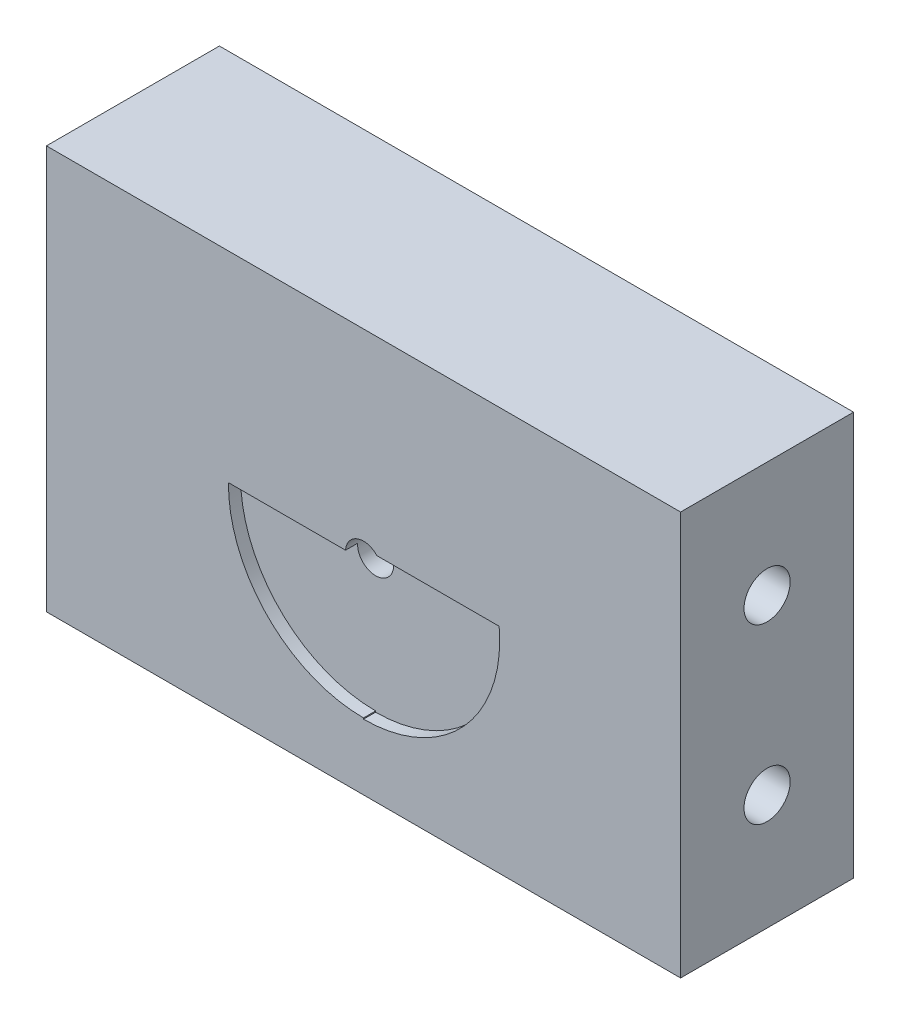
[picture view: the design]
ISO-10303-21;
HEADER;
FILE_DESCRIPTION(('STEP AP214'),'2;1');
FILE_NAME('part.step','',(''),(''),'','','');
FILE_SCHEMA(('AUTOMOTIVE_DESIGN { 1 0 10303 214 1 1 1 1 }'));
ENDSEC;
DATA;
#1=APPLICATION_CONTEXT('core data for automotive mechanical design processes');
#2=APPLICATION_PROTOCOL_DEFINITION('international standard','automotive_design',2000,#1);
#3=PRODUCT_CONTEXT('',#1,'mechanical');
#4=PRODUCT('Part','Part','',(#3));
#5=PRODUCT_RELATED_PRODUCT_CATEGORY('part','',(#4));
#6=PRODUCT_DEFINITION_FORMATION('','',#4);
#7=PRODUCT_DEFINITION_CONTEXT('part definition',#1,'design');
#8=PRODUCT_DEFINITION('design','',#6,#7);
#9=PRODUCT_DEFINITION_SHAPE('','',#8);
#10=(LENGTH_UNIT() NAMED_UNIT(*) SI_UNIT(.MILLI.,.METRE.));
#11=(NAMED_UNIT(*) PLANE_ANGLE_UNIT() SI_UNIT($,.RADIAN.));
#12=(NAMED_UNIT(*) SI_UNIT($,.STERADIAN.) SOLID_ANGLE_UNIT());
#13=UNCERTAINTY_MEASURE_WITH_UNIT(LENGTH_MEASURE(1.E-05),#10,'distance_accuracy_value','');
#14=(GEOMETRIC_REPRESENTATION_CONTEXT(3) GLOBAL_UNCERTAINTY_ASSIGNED_CONTEXT((#13)) GLOBAL_UNIT_ASSIGNED_CONTEXT((#10,
#11,#12)) REPRESENTATION_CONTEXT('',''));
#15=CARTESIAN_POINT('',(0.,0.,0.));
#16=DIRECTION('',(0.,0.,1.));
#17=DIRECTION('',(1.,0.,0.));
#18=AXIS2_PLACEMENT_3D('',#15,#16,#17);
#19=CARTESIAN_POINT('',(0.360795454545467,0.,-6.35));
#20=DIRECTION('',(0.,0.,1.));
#21=DIRECTION('',(1.,0.,0.));
#22=AXIS2_PLACEMENT_3D('',#19,#20,#21);
#23=PLANE('',#22);
#24=CARTESIAN_POINT('',(0.,0.,-6.35000000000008));
#25=DIRECTION('',(0.,0.,-1.));
#26=DIRECTION('',(-1.,0.,0.));
#27=AXIS2_PLACEMENT_3D('',#24,#25,#26);
#28=CIRCLE('',#27,3.96875000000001);
#29=CARTESIAN_POINT('',(-3.96875000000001,0.,-6.35000000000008));
#30=VERTEX_POINT('',#29);
#31=EDGE_CURVE('E154',#30,#30,#28,.F.);
#32=ORIENTED_EDGE('',*,*,#31,.T.);
#33=EDGE_LOOP('',(#32));
#34=FACE_BOUND('',#33,.T.);
#35=ADVANCED_FACE('F33',(#34),#23,.T.);
#36=CARTESIAN_POINT('',(-67.31,0.386772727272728,7.62));
#37=DIRECTION('',(1.,0.,0.));
#38=DIRECTION('',(0.,0.,-1.));
#39=AXIS2_PLACEMENT_3D('',#36,#37,#38);
#40=PLANE('',#39);
#41=CARTESIAN_POINT('',(-67.31,0.,7.62));
#42=DIRECTION('',(1.,0.,0.));
#43=DIRECTION('',(0.,0.,-1.));
#44=AXIS2_PLACEMENT_3D('',#41,#42,#43);
#45=CIRCLE('',#44,4.25450000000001);
#46=CARTESIAN_POINT('',(-67.31,0.,3.36549999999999));
#47=VERTEX_POINT('',#46);
#48=EDGE_CURVE('E292',#47,#47,#45,.F.);
#49=ORIENTED_EDGE('',*,*,#48,.T.);
#50=EDGE_LOOP('',(#49));
#51=FACE_BOUND('',#50,.T.);
#52=ADVANCED_FACE('F321',(#51),#40,.F.);
#53=CARTESIAN_POINT('',(-65.278,-9.80209090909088,0.));
#54=DIRECTION('',(1.,0.,0.));
#55=DIRECTION('',(0.,0.,-1.));
#56=AXIS2_PLACEMENT_3D('',#53,#54,#55);
#57=PLANE('',#56);
#58=CARTESIAN_POINT('',(-65.278,-10.16,0.));
#59=DIRECTION('',(1.,0.,0.));
#60=DIRECTION('',(0.,0.,-1.));
#61=AXIS2_PLACEMENT_3D('',#58,#59,#60);
#62=CIRCLE('',#61,3.93700000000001);
#63=CARTESIAN_POINT('',(-65.278,-10.16,-3.93700000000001));
#64=VERTEX_POINT('',#63);
#65=EDGE_CURVE('E289',#64,#64,#62,.F.);
#66=ORIENTED_EDGE('',*,*,#65,.T.);
#67=EDGE_LOOP('',(#66));
#68=FACE_BOUND('',#67,.T.);
#69=ADVANCED_FACE('F326',(#68),#57,.F.);
#70=CARTESIAN_POINT('',(-65.278,10.5179090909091,0.));
#71=DIRECTION('',(1.,0.,0.));
#72=DIRECTION('',(0.,0.,-1.));
#73=AXIS2_PLACEMENT_3D('',#70,#71,#72);
#74=PLANE('',#73);
#75=CARTESIAN_POINT('',(-65.278,10.16,0.));
#76=DIRECTION('',(1.,0.,0.));
#77=DIRECTION('',(0.,0.,-1.));
#78=AXIS2_PLACEMENT_3D('',#75,#76,#77);
#79=CIRCLE('',#78,3.93700000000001);
#80=CARTESIAN_POINT('',(-65.278,10.16,-3.93700000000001));
#81=VERTEX_POINT('',#80);
#82=EDGE_CURVE('E286',#81,#81,#79,.F.);
#83=ORIENTED_EDGE('',*,*,#82,.T.);
#84=EDGE_LOOP('',(#83));
#85=FACE_BOUND('',#84,.T.);
#86=ADVANCED_FACE('F725',(#85),#74,.F.);
#87=CARTESIAN_POINT('',(-67.31,0.386772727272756,-7.62));
#88=DIRECTION('',(1.,0.,0.));
#89=DIRECTION('',(0.,0.,-1.));
#90=AXIS2_PLACEMENT_3D('',#87,#88,#89);
#91=PLANE('',#90);
#92=CARTESIAN_POINT('',(-67.31,0.,-7.62));
#93=DIRECTION('',(1.,0.,0.));
#94=DIRECTION('',(0.,0.,-1.));
#95=AXIS2_PLACEMENT_3D('',#92,#93,#94);
#96=CIRCLE('',#95,4.25450000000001);
#97=CARTESIAN_POINT('',(-67.31,0.,-11.8745));
#98=VERTEX_POINT('',#97);
#99=EDGE_CURVE('E283',#98,#98,#96,.F.);
#100=ORIENTED_EDGE('',*,*,#99,.T.);
#101=EDGE_LOOP('',(#100));
#102=FACE_BOUND('',#101,.T.);
#103=ADVANCED_FACE('F716',(#102),#91,.F.);
#104=CARTESIAN_POINT('',(-67.31,-39.3007272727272,5.08000000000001));
#105=DIRECTION('',(1.,0.,0.));
#106=DIRECTION('',(0.,0.,-1.));
#107=AXIS2_PLACEMENT_3D('',#104,#105,#106);
#108=PLANE('',#107);
#109=CARTESIAN_POINT('',(-67.31,-39.6875,5.08000000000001));
#110=DIRECTION('',(1.,0.,0.));
#111=DIRECTION('',(0.,0.,-1.));
#112=AXIS2_PLACEMENT_3D('',#109,#110,#111);
#113=CIRCLE('',#112,4.25450000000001);
#114=CARTESIAN_POINT('',(-67.31,-39.6875,0.825500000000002));
#115=VERTEX_POINT('',#114);
#116=EDGE_CURVE('E280',#115,#115,#113,.F.);
#117=ORIENTED_EDGE('',*,*,#116,.T.);
#118=EDGE_LOOP('',(#117));
#119=FACE_BOUND('',#118,.T.);
#120=ADVANCED_FACE('F711',(#119),#108,.F.);
#121=CARTESIAN_POINT('',(-67.31,40.0742727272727,5.08000000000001));
#122=DIRECTION('',(1.,0.,0.));
#123=DIRECTION('',(0.,0.,-1.));
#124=AXIS2_PLACEMENT_3D('',#121,#122,#123);
#125=PLANE('',#124);
#126=CARTESIAN_POINT('',(-67.31,39.6875,5.08000000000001));
#127=DIRECTION('',(1.,0.,0.));
#128=DIRECTION('',(0.,0.,-1.));
#129=AXIS2_PLACEMENT_3D('',#126,#127,#128);
#130=CIRCLE('',#129,4.25450000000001);
#131=CARTESIAN_POINT('',(-67.31,39.6875,0.825500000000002));
#132=VERTEX_POINT('',#131);
#133=EDGE_CURVE('E277',#132,#132,#130,.F.);
#134=ORIENTED_EDGE('',*,*,#133,.T.);
#135=EDGE_LOOP('',(#134));
#136=FACE_BOUND('',#135,.T.);
#137=ADVANCED_FACE('F715',(#136),#125,.F.);
#138=CARTESIAN_POINT('',(-67.31,40.0742727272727,-5.08));
#139=DIRECTION('',(1.,0.,0.));
#140=DIRECTION('',(0.,0.,-1.));
#141=AXIS2_PLACEMENT_3D('',#138,#139,#140);
#142=PLANE('',#141);
#143=CARTESIAN_POINT('',(-67.31,39.6875,-5.08));
#144=DIRECTION('',(1.,0.,0.));
#145=DIRECTION('',(0.,0.,-1.));
#146=AXIS2_PLACEMENT_3D('',#143,#144,#145);
#147=CIRCLE('',#146,4.25450000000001);
#148=CARTESIAN_POINT('',(-67.31,39.6875,-9.33450000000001));
#149=VERTEX_POINT('',#148);
#150=EDGE_CURVE('E274',#149,#149,#147,.F.);
#151=ORIENTED_EDGE('',*,*,#150,.T.);
#152=EDGE_LOOP('',(#151));
#153=FACE_BOUND('',#152,.T.);
#154=ADVANCED_FACE('F770',(#153),#142,.F.);
#155=CARTESIAN_POINT('',(-67.31,-39.3007272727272,-5.08));
#156=DIRECTION('',(1.,0.,0.));
#157=DIRECTION('',(0.,0.,-1.));
#158=AXIS2_PLACEMENT_3D('',#155,#156,#157);
#159=PLANE('',#158);
#160=CARTESIAN_POINT('',(-67.31,-39.6875,-5.08));
#161=DIRECTION('',(1.,0.,0.));
#162=DIRECTION('',(0.,0.,-1.));
#163=AXIS2_PLACEMENT_3D('',#160,#161,#162);
#164=CIRCLE('',#163,4.25450000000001);
#165=CARTESIAN_POINT('',(-67.31,-39.6875,-9.33450000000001));
#166=VERTEX_POINT('',#165);
#167=EDGE_CURVE('E271',#166,#166,#164,.F.);
#168=ORIENTED_EDGE('',*,*,#167,.T.);
#169=EDGE_LOOP('',(#168));
#170=FACE_BOUND('',#169,.T.);
#171=ADVANCED_FACE('F350',(#170),#159,.F.);
#172=CARTESIAN_POINT('',(-66.802,-27.94,5.1816));
#173=DIRECTION('',(1.,0.,0.));
#174=DIRECTION('',(0.,0.,-1.));
#175=AXIS2_PLACEMENT_3D('',#172,#173,#174);
#176=PLANE('',#175);
#177=CARTESIAN_POINT('',(-66.802,-22.86,0.));
#178=DIRECTION('',(1.,0.,0.));
#179=DIRECTION('',(0.,0.,-1.));
#180=AXIS2_PLACEMENT_3D('',#177,#178,#179);
#181=CIRCLE('',#180,5.08);
#182=CARTESIAN_POINT('',(-66.802,-22.86,-5.08));
#183=VERTEX_POINT('',#182);
#184=EDGE_CURVE('E268',#183,#183,#181,.F.);
#185=ORIENTED_EDGE('',*,*,#184,.T.);
#186=EDGE_LOOP('',(#185));
#187=FACE_BOUND('',#186,.T.);
#188=ADVANCED_FACE('F347',(#187),#176,.F.);
#189=CARTESIAN_POINT('',(-66.802,23.3218181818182,0.));
#190=DIRECTION('',(1.,0.,0.));
#191=DIRECTION('',(0.,0.,-1.));
#192=AXIS2_PLACEMENT_3D('',#189,#190,#191);
#193=PLANE('',#192);
#194=CARTESIAN_POINT('',(-66.802,22.86,0.));
#195=DIRECTION('',(1.,0.,0.));
#196=DIRECTION('',(0.,0.,-1.));
#197=AXIS2_PLACEMENT_3D('',#194,#195,#196);
#198=CIRCLE('',#197,5.08);
#199=CARTESIAN_POINT('',(-66.802,22.86,-5.08));
#200=VERTEX_POINT('',#199);
#201=EDGE_CURVE('E265',#200,#200,#198,.F.);
#202=ORIENTED_EDGE('',*,*,#201,.T.);
#203=EDGE_LOOP('',(#202));
#204=FACE_BOUND('',#203,.T.);
#205=ADVANCED_FACE('F316',(#204),#193,.F.);
#206=CARTESIAN_POINT('',(0.,0.,19.05));
#207=DIRECTION('',(0.,0.,-1.));
#208=DIRECTION('',(-1.,0.,0.));
#209=AXIS2_PLACEMENT_3D('',#206,#207,#208);
#210=CYLINDRICAL_SURFACE('',#209,3.96875000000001);
#211=CARTESIAN_POINT('',(0.,0.,19.05));
#212=DIRECTION('',(0.,0.,-1.));
#213=DIRECTION('',(-1.,0.,0.));
#214=AXIS2_PLACEMENT_3D('',#211,#212,#213);
#215=CIRCLE('',#214,3.96875000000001);
#216=CARTESIAN_POINT('',(-3.96061365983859,0.253999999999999,19.05));
#217=VERTEX_POINT('',#216);
#218=CARTESIAN_POINT('',(2.93906236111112,2.667,19.05));
#219=VERTEX_POINT('',#218);
#220=EDGE_CURVE('E263',#217,#219,#215,.T.);
#221=ORIENTED_EDGE('',*,*,#220,.F.);
#222=DIRECTION('',(0.,0.,-1.));
#223=VECTOR('',#222,1.);
#224=CARTESIAN_POINT('',(-3.96061365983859,0.253999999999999,19.05));
#225=LINE('',#224,#223);
#226=CARTESIAN_POINT('',(-3.96061365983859,0.253999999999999,16.383));
#227=VERTEX_POINT('',#226);
#228=EDGE_CURVE('E125',#217,#227,#225,.T.);
#229=ORIENTED_EDGE('',*,*,#228,.T.);
#230=CARTESIAN_POINT('',(0.,0.,16.383));
#231=DIRECTION('',(0.,0.,1.));
#232=DIRECTION('',(1.,0.,0.));
#233=AXIS2_PLACEMENT_3D('',#230,#231,#232);
#234=CIRCLE('',#233,3.96875000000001);
#235=CARTESIAN_POINT('',(2.93906236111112,2.667,16.383));
#236=VERTEX_POINT('',#235);
#237=EDGE_CURVE('E41',#236,#227,#234,.F.);
#238=ORIENTED_EDGE('',*,*,#237,.F.);
#239=DIRECTION('',(0.,0.,-1.));
#240=VECTOR('',#239,1.);
#241=CARTESIAN_POINT('',(2.93906236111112,2.667,19.05));
#242=LINE('',#241,#240);
#243=EDGE_CURVE('E150',#236,#219,#242,.F.);
#244=ORIENTED_EDGE('',*,*,#243,.T.);
#245=EDGE_LOOP('',(#221,#229,#238,#244));
#246=FACE_BOUND('',#245,.T.);
#247=ORIENTED_EDGE('',*,*,#31,.F.);
#248=EDGE_LOOP('',(#247));
#249=FACE_BOUND('',#248,.T.);
#250=ADVANCED_FACE('F312',(#246,#249),#210,.F.);
#251=CARTESIAN_POINT('',(39.116,13.97,5.1816));
#252=DIRECTION('',(1.,0.,0.));
#253=DIRECTION('',(0.,0.,-1.));
#254=AXIS2_PLACEMENT_3D('',#251,#252,#253);
#255=PLANE('',#254);
#256=CARTESIAN_POINT('',(39.116,19.05,0.));
#257=DIRECTION('',(-1.,0.,0.));
#258=DIRECTION('',(0.,0.,1.));
#259=AXIS2_PLACEMENT_3D('',#256,#257,#258);
#260=CIRCLE('',#259,5.08);
#261=CARTESIAN_POINT('',(39.116,19.05,5.08));
#262=VERTEX_POINT('',#261);
#263=EDGE_CURVE('E260',#262,#262,#260,.F.);
#264=ORIENTED_EDGE('',*,*,#263,.T.);
#265=EDGE_LOOP('',(#264));
#266=FACE_BOUND('',#265,.T.);
#267=ADVANCED_FACE('F315',(#266),#255,.T.);
#268=CARTESIAN_POINT('',(39.116,-18.5881818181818,0.));
#269=DIRECTION('',(1.,0.,0.));
#270=DIRECTION('',(0.,0.,-1.));
#271=AXIS2_PLACEMENT_3D('',#268,#269,#270);
#272=PLANE('',#271);
#273=CARTESIAN_POINT('',(39.116,-19.05,0.));
#274=DIRECTION('',(-1.,0.,0.));
#275=DIRECTION('',(0.,0.,1.));
#276=AXIS2_PLACEMENT_3D('',#273,#274,#275);
#277=CIRCLE('',#276,5.08);
#278=CARTESIAN_POINT('',(39.116,-19.05,5.08));
#279=VERTEX_POINT('',#278);
#280=EDGE_CURVE('E158',#279,#279,#277,.F.);
#281=ORIENTED_EDGE('',*,*,#280,.T.);
#282=EDGE_LOOP('',(#281));
#283=FACE_BOUND('',#282,.T.);
#284=ADVANCED_FACE('F353',(#283),#272,.T.);
#285=CARTESIAN_POINT('',(-69.85,0.,7.62));
#286=DIRECTION('',(1.,0.,0.));
#287=DIRECTION('',(0.,0.,-1.));
#288=AXIS2_PLACEMENT_3D('',#285,#286,#287);
#289=CYLINDRICAL_SURFACE('',#288,4.25450000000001);
#290=CARTESIAN_POINT('',(-69.85,0.,7.62));
#291=DIRECTION('',(1.,0.,0.));
#292=DIRECTION('',(0.,0.,-1.));
#293=AXIS2_PLACEMENT_3D('',#290,#291,#292);
#294=CIRCLE('',#293,4.25450000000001);
#295=CARTESIAN_POINT('',(-69.85,0.,3.36549999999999));
#296=VERTEX_POINT('',#295);
#297=EDGE_CURVE('E161',#296,#296,#294,.T.);
#298=ORIENTED_EDGE('',*,*,#297,.F.);
#299=EDGE_LOOP('',(#298));
#300=FACE_BOUND('',#299,.T.);
#301=ORIENTED_EDGE('',*,*,#48,.F.);
#302=EDGE_LOOP('',(#301));
#303=FACE_BOUND('',#302,.T.);
#304=ADVANCED_FACE('F590',(#300,#303),#289,.F.);
#305=CARTESIAN_POINT('',(-69.85,-10.16,0.));
#306=DIRECTION('',(1.,0.,0.));
#307=DIRECTION('',(0.,0.,-1.));
#308=AXIS2_PLACEMENT_3D('',#305,#306,#307);
#309=CYLINDRICAL_SURFACE('',#308,3.93700000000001);
#310=CARTESIAN_POINT('',(-69.85,-10.16,0.));
#311=DIRECTION('',(1.,0.,0.));
#312=DIRECTION('',(0.,0.,-1.));
#313=AXIS2_PLACEMENT_3D('',#310,#311,#312);
#314=CIRCLE('',#313,3.93700000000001);
#315=CARTESIAN_POINT('',(-69.85,-10.16,-3.93700000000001));
#316=VERTEX_POINT('',#315);
#317=EDGE_CURVE('E253',#316,#316,#314,.T.);
#318=ORIENTED_EDGE('',*,*,#317,.F.);
#319=EDGE_LOOP('',(#318));
#320=FACE_BOUND('',#319,.T.);
#321=ORIENTED_EDGE('',*,*,#65,.F.);
#322=EDGE_LOOP('',(#321));
#323=FACE_BOUND('',#322,.T.);
#324=ADVANCED_FACE('F601',(#320,#323),#309,.F.);
#325=CARTESIAN_POINT('',(-69.85,10.16,0.));
#326=DIRECTION('',(1.,0.,0.));
#327=DIRECTION('',(0.,0.,-1.));
#328=AXIS2_PLACEMENT_3D('',#325,#326,#327);
#329=CYLINDRICAL_SURFACE('',#328,3.93700000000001);
#330=CARTESIAN_POINT('',(-69.85,10.16,0.));
#331=DIRECTION('',(1.,0.,0.));
#332=DIRECTION('',(0.,0.,-1.));
#333=AXIS2_PLACEMENT_3D('',#330,#331,#332);
#334=CIRCLE('',#333,3.93700000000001);
#335=CARTESIAN_POINT('',(-69.85,10.16,-3.93700000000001));
#336=VERTEX_POINT('',#335);
#337=EDGE_CURVE('E250',#336,#336,#334,.T.);
#338=ORIENTED_EDGE('',*,*,#337,.F.);
#339=EDGE_LOOP('',(#338));
#340=FACE_BOUND('',#339,.T.);
#341=ORIENTED_EDGE('',*,*,#82,.F.);
#342=EDGE_LOOP('',(#341));
#343=FACE_BOUND('',#342,.T.);
#344=ADVANCED_FACE('F610',(#340,#343),#329,.F.);
#345=CARTESIAN_POINT('',(-69.85,0.,-7.62));
#346=DIRECTION('',(1.,0.,0.));
#347=DIRECTION('',(0.,0.,-1.));
#348=AXIS2_PLACEMENT_3D('',#345,#346,#347);
#349=CYLINDRICAL_SURFACE('',#348,4.25450000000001);
#350=CARTESIAN_POINT('',(-69.85,0.,-7.62));
#351=DIRECTION('',(1.,0.,0.));
#352=DIRECTION('',(0.,0.,-1.));
#353=AXIS2_PLACEMENT_3D('',#350,#351,#352);
#354=CIRCLE('',#353,4.25450000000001);
#355=CARTESIAN_POINT('',(-69.85,0.,-11.8745));
#356=VERTEX_POINT('',#355);
#357=EDGE_CURVE('E247',#356,#356,#354,.T.);
#358=ORIENTED_EDGE('',*,*,#357,.F.);
#359=EDGE_LOOP('',(#358));
#360=FACE_BOUND('',#359,.T.);
#361=ORIENTED_EDGE('',*,*,#99,.F.);
#362=EDGE_LOOP('',(#361));
#363=FACE_BOUND('',#362,.T.);
#364=ADVANCED_FACE('F618',(#360,#363),#349,.F.);
#365=CARTESIAN_POINT('',(-69.85,-39.6875,5.08000000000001));
#366=DIRECTION('',(1.,0.,0.));
#367=DIRECTION('',(0.,0.,-1.));
#368=AXIS2_PLACEMENT_3D('',#365,#366,#367);
#369=CYLINDRICAL_SURFACE('',#368,4.25450000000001);
#370=CARTESIAN_POINT('',(-69.85,-39.6875,5.08000000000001));
#371=DIRECTION('',(1.,0.,0.));
#372=DIRECTION('',(0.,0.,-1.));
#373=AXIS2_PLACEMENT_3D('',#370,#371,#372);
#374=CIRCLE('',#373,4.25450000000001);
#375=CARTESIAN_POINT('',(-69.85,-39.6875,0.825500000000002));
#376=VERTEX_POINT('',#375);
#377=EDGE_CURVE('E244',#376,#376,#374,.T.);
#378=ORIENTED_EDGE('',*,*,#377,.F.);
#379=EDGE_LOOP('',(#378));
#380=FACE_BOUND('',#379,.T.);
#381=ORIENTED_EDGE('',*,*,#116,.F.);
#382=EDGE_LOOP('',(#381));
#383=FACE_BOUND('',#382,.T.);
#384=ADVANCED_FACE('F627',(#380,#383),#369,.F.);
#385=CARTESIAN_POINT('',(-69.85,39.6875,5.08000000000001));
#386=DIRECTION('',(1.,0.,0.));
#387=DIRECTION('',(0.,0.,-1.));
#388=AXIS2_PLACEMENT_3D('',#385,#386,#387);
#389=CYLINDRICAL_SURFACE('',#388,4.25450000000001);
#390=CARTESIAN_POINT('',(-69.85,39.6875,5.08000000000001));
#391=DIRECTION('',(1.,0.,0.));
#392=DIRECTION('',(0.,0.,-1.));
#393=AXIS2_PLACEMENT_3D('',#390,#391,#392);
#394=CIRCLE('',#393,4.25450000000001);
#395=CARTESIAN_POINT('',(-69.85,39.6875,0.825500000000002));
#396=VERTEX_POINT('',#395);
#397=EDGE_CURVE('E241',#396,#396,#394,.T.);
#398=ORIENTED_EDGE('',*,*,#397,.F.);
#399=EDGE_LOOP('',(#398));
#400=FACE_BOUND('',#399,.T.);
#401=ORIENTED_EDGE('',*,*,#133,.F.);
#402=EDGE_LOOP('',(#401));
#403=FACE_BOUND('',#402,.T.);
#404=ADVANCED_FACE('F636',(#400,#403),#389,.F.);
#405=CARTESIAN_POINT('',(-69.85,39.6875,-5.08));
#406=DIRECTION('',(1.,0.,0.));
#407=DIRECTION('',(0.,0.,-1.));
#408=AXIS2_PLACEMENT_3D('',#405,#406,#407);
#409=CYLINDRICAL_SURFACE('',#408,4.25450000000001);
#410=CARTESIAN_POINT('',(-69.85,39.6875,-5.08));
#411=DIRECTION('',(1.,0.,0.));
#412=DIRECTION('',(0.,0.,-1.));
#413=AXIS2_PLACEMENT_3D('',#410,#411,#412);
#414=CIRCLE('',#413,4.25450000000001);
#415=CARTESIAN_POINT('',(-69.85,39.6875,-9.33450000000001));
#416=VERTEX_POINT('',#415);
#417=EDGE_CURVE('E238',#416,#416,#414,.T.);
#418=ORIENTED_EDGE('',*,*,#417,.F.);
#419=EDGE_LOOP('',(#418));
#420=FACE_BOUND('',#419,.T.);
#421=ORIENTED_EDGE('',*,*,#150,.F.);
#422=EDGE_LOOP('',(#421));
#423=FACE_BOUND('',#422,.T.);
#424=ADVANCED_FACE('F366',(#420,#423),#409,.F.);
#425=CARTESIAN_POINT('',(-69.85,-39.6875,-5.08));
#426=DIRECTION('',(1.,0.,0.));
#427=DIRECTION('',(0.,0.,-1.));
#428=AXIS2_PLACEMENT_3D('',#425,#426,#427);
#429=CYLINDRICAL_SURFACE('',#428,4.25450000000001);
#430=CARTESIAN_POINT('',(-69.85,-39.6875,-5.08));
#431=DIRECTION('',(1.,0.,0.));
#432=DIRECTION('',(0.,0.,-1.));
#433=AXIS2_PLACEMENT_3D('',#430,#431,#432);
#434=CIRCLE('',#433,4.25450000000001);
#435=CARTESIAN_POINT('',(-69.85,-39.6875,-9.33450000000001));
#436=VERTEX_POINT('',#435);
#437=EDGE_CURVE('E235',#436,#436,#434,.T.);
#438=ORIENTED_EDGE('',*,*,#437,.F.);
#439=EDGE_LOOP('',(#438));
#440=FACE_BOUND('',#439,.T.);
#441=ORIENTED_EDGE('',*,*,#167,.F.);
#442=EDGE_LOOP('',(#441));
#443=FACE_BOUND('',#442,.T.);
#444=ADVANCED_FACE('F358',(#440,#443),#429,.F.);
#445=CARTESIAN_POINT('',(-69.85,-22.86,0.));
#446=DIRECTION('',(1.,0.,0.));
#447=DIRECTION('',(0.,0.,-1.));
#448=AXIS2_PLACEMENT_3D('',#445,#446,#447);
#449=CYLINDRICAL_SURFACE('',#448,5.08);
#450=ORIENTED_EDGE('',*,*,#184,.F.);
#451=EDGE_LOOP('',(#450));
#452=FACE_BOUND('',#451,.T.);
#453=CARTESIAN_POINT('',(-69.85,-22.86,0.));
#454=DIRECTION('',(1.,0.,0.));
#455=DIRECTION('',(0.,0.,-1.));
#456=AXIS2_PLACEMENT_3D('',#453,#454,#455);
#457=CIRCLE('',#456,5.08);
#458=CARTESIAN_POINT('',(-69.85,-22.86,-5.08));
#459=VERTEX_POINT('',#458);
#460=EDGE_CURVE('E232',#459,#459,#457,.T.);
#461=ORIENTED_EDGE('',*,*,#460,.F.);
#462=EDGE_LOOP('',(#461));
#463=FACE_BOUND('',#462,.T.);
#464=ADVANCED_FACE('F355',(#452,#463),#449,.F.);
#465=CARTESIAN_POINT('',(-69.85,22.86,0.));
#466=DIRECTION('',(1.,0.,0.));
#467=DIRECTION('',(0.,0.,-1.));
#468=AXIS2_PLACEMENT_3D('',#465,#466,#467);
#469=CYLINDRICAL_SURFACE('',#468,5.08);
#470=ORIENTED_EDGE('',*,*,#201,.F.);
#471=EDGE_LOOP('',(#470));
#472=FACE_BOUND('',#471,.T.);
#473=CARTESIAN_POINT('',(-69.85,22.86,0.));
#474=DIRECTION('',(1.,0.,0.));
#475=DIRECTION('',(0.,0.,-1.));
#476=AXIS2_PLACEMENT_3D('',#473,#474,#475);
#477=CIRCLE('',#476,5.08);
#478=CARTESIAN_POINT('',(-69.85,22.86,-5.08));
#479=VERTEX_POINT('',#478);
#480=EDGE_CURVE('E168',#479,#479,#477,.T.);
#481=ORIENTED_EDGE('',*,*,#480,.F.);
#482=EDGE_LOOP('',(#481));
#483=FACE_BOUND('',#482,.T.);
#484=ADVANCED_FACE('F357',(#472,#483),#469,.F.);
#485=CARTESIAN_POINT('',(0.,0.,19.05));
#486=DIRECTION('',(0.,0.,1.));
#487=DIRECTION('',(1.,0.,0.));
#488=AXIS2_PLACEMENT_3D('',#485,#486,#487);
#489=PLANE('',#488);
#490=CARTESIAN_POINT('',(0.,0.,19.05));
#491=DIRECTION('',(0.,0.,1.));
#492=DIRECTION('',(1.,0.,0.));
#493=AXIS2_PLACEMENT_3D('',#490,#491,#492);
#494=CIRCLE('',#493,29.7560228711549);
#495=CARTESIAN_POINT('',(-29.7549387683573,0.253999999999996,19.05));
#496=VERTEX_POINT('',#495);
#497=CARTESIAN_POINT('',(0.,-29.7560228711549,19.05));
#498=VERTEX_POINT('',#497);
#499=EDGE_CURVE('E116',#496,#498,#494,.T.);
#500=ORIENTED_EDGE('',*,*,#499,.F.);
#501=DIRECTION('',(-1.,0.,0.));
#502=VECTOR('',#501,1.);
#503=CARTESIAN_POINT('',(2.93906236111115,0.254,19.05));
#504=LINE('',#503,#502);
#505=EDGE_CURVE('E122',#217,#496,#504,.T.);
#506=ORIENTED_EDGE('',*,*,#505,.F.);
#507=ORIENTED_EDGE('',*,*,#220,.T.);
#508=DIRECTION('',(-1.,0.,0.));
#509=VECTOR('',#508,1.);
#510=CARTESIAN_POINT('',(0.,2.667,19.05));
#511=LINE('',#510,#509);
#512=CARTESIAN_POINT('',(29.8812166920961,2.667,19.05));
#513=VERTEX_POINT('',#512);
#514=EDGE_CURVE('E140',#513,#219,#511,.T.);
#515=ORIENTED_EDGE('',*,*,#514,.F.);
#516=CARTESIAN_POINT('',(0.,0.,19.05));
#517=DIRECTION('',(0.,0.,1.));
#518=DIRECTION('',(1.,0.,0.));
#519=AXIS2_PLACEMENT_3D('',#516,#517,#518);
#520=CIRCLE('',#519,30.);
#521=CARTESIAN_POINT('',(0.,-30.,19.05));
#522=VERTEX_POINT('',#521);
#523=EDGE_CURVE('E56',#522,#513,#520,.T.);
#524=ORIENTED_EDGE('',*,*,#523,.F.);
#525=DIRECTION('',(0.,-1.,0.));
#526=VECTOR('',#525,1.);
#527=CARTESIAN_POINT('',(0.,0.,19.05));
#528=LINE('',#527,#526);
#529=EDGE_CURVE('E193',#498,#522,#528,.T.);
#530=ORIENTED_EDGE('',*,*,#529,.F.);
#531=EDGE_LOOP('',(#500,#506,#507,#515,#524,#530));
#532=FACE_BOUND('',#531,.T.);
#533=DIRECTION('',(0.,1.,0.));
#534=VECTOR('',#533,1.);
#535=CARTESIAN_POINT('',(69.85,44.45,19.05));
#536=LINE('',#535,#534);
#537=CARTESIAN_POINT('',(69.85,44.45,19.05));
#538=VERTEX_POINT('',#537);
#539=CARTESIAN_POINT('',(69.85,-44.45,19.05));
#540=VERTEX_POINT('',#539);
#541=EDGE_CURVE('E165',#538,#540,#536,.F.);
#542=ORIENTED_EDGE('',*,*,#541,.F.);
#543=DIRECTION('',(1.,0.,0.));
#544=VECTOR('',#543,1.);
#545=CARTESIAN_POINT('',(-69.85,44.45,19.05));
#546=LINE('',#545,#544);
#547=CARTESIAN_POINT('',(-69.85,44.45,19.05));
#548=VERTEX_POINT('',#547);
#549=EDGE_CURVE('E155',#548,#538,#546,.T.);
#550=ORIENTED_EDGE('',*,*,#549,.F.);
#551=DIRECTION('',(0.,1.,0.));
#552=VECTOR('',#551,1.);
#553=CARTESIAN_POINT('',(-69.85,-44.45,19.05));
#554=LINE('',#553,#552);
#555=CARTESIAN_POINT('',(-69.85,-44.45,19.05));
#556=VERTEX_POINT('',#555);
#557=EDGE_CURVE('E157',#556,#548,#554,.T.);
#558=ORIENTED_EDGE('',*,*,#557,.F.);
#559=DIRECTION('',(1.,0.,0.));
#560=VECTOR('',#559,1.);
#561=CARTESIAN_POINT('',(69.85,-44.45,19.05));
#562=LINE('',#561,#560);
#563=EDGE_CURVE('E166',#540,#556,#562,.F.);
#564=ORIENTED_EDGE('',*,*,#563,.F.);
#565=EDGE_LOOP('',(#542,#550,#558,#564));
#566=FACE_BOUND('',#565,.T.);
#567=ADVANCED_FACE('F305',(#532,#566),#489,.T.);
#568=CARTESIAN_POINT('',(69.85,19.05,0.));
#569=DIRECTION('',(-1.,0.,0.));
#570=DIRECTION('',(0.,0.,1.));
#571=AXIS2_PLACEMENT_3D('',#568,#569,#570);
#572=CYLINDRICAL_SURFACE('',#571,5.08);
#573=ORIENTED_EDGE('',*,*,#263,.F.);
#574=EDGE_LOOP('',(#573));
#575=FACE_BOUND('',#574,.T.);
#576=CARTESIAN_POINT('',(69.85,19.05,0.));
#577=DIRECTION('',(-1.,0.,0.));
#578=DIRECTION('',(0.,0.,1.));
#579=AXIS2_PLACEMENT_3D('',#576,#577,#578);
#580=CIRCLE('',#579,5.08);
#581=CARTESIAN_POINT('',(69.85,19.05,5.08));
#582=VERTEX_POINT('',#581);
#583=EDGE_CURVE('E172',#582,#582,#580,.T.);
#584=ORIENTED_EDGE('',*,*,#583,.F.);
#585=EDGE_LOOP('',(#584));
#586=FACE_BOUND('',#585,.T.);
#587=ADVANCED_FACE('F35',(#575,#586),#572,.F.);
#588=CARTESIAN_POINT('',(69.85,-19.05,0.));
#589=DIRECTION('',(-1.,0.,0.));
#590=DIRECTION('',(0.,0.,1.));
#591=AXIS2_PLACEMENT_3D('',#588,#589,#590);
#592=CYLINDRICAL_SURFACE('',#591,5.08);
#593=ORIENTED_EDGE('',*,*,#280,.F.);
#594=EDGE_LOOP('',(#593));
#595=FACE_BOUND('',#594,.T.);
#596=CARTESIAN_POINT('',(69.85,-19.05,0.));
#597=DIRECTION('',(-1.,0.,0.));
#598=DIRECTION('',(0.,0.,1.));
#599=AXIS2_PLACEMENT_3D('',#596,#597,#598);
#600=CIRCLE('',#599,5.08);
#601=CARTESIAN_POINT('',(69.85,-19.05,5.08));
#602=VERTEX_POINT('',#601);
#603=EDGE_CURVE('E225',#602,#602,#600,.T.);
#604=ORIENTED_EDGE('',*,*,#603,.F.);
#605=EDGE_LOOP('',(#604));
#606=FACE_BOUND('',#605,.T.);
#607=ADVANCED_FACE('F417',(#595,#606),#592,.F.);
#608=CARTESIAN_POINT('',(-37.7392045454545,38.1,-0.1524));
#609=DIRECTION('',(0.,0.,1.));
#610=DIRECTION('',(1.,0.,0.));
#611=AXIS2_PLACEMENT_3D('',#608,#609,#610);
#612=PLANE('',#611);
#613=CARTESIAN_POINT('',(-38.1,38.1,-0.1524));
#614=DIRECTION('',(0.,0.,-1.));
#615=DIRECTION('',(-1.,0.,0.));
#616=AXIS2_PLACEMENT_3D('',#613,#614,#615);
#617=CIRCLE('',#616,3.96875);
#618=CARTESIAN_POINT('',(-42.06875,38.1,-0.1524));
#619=VERTEX_POINT('',#618);
#620=EDGE_CURVE('E222',#619,#619,#617,.T.);
#621=ORIENTED_EDGE('',*,*,#620,.T.);
#622=EDGE_LOOP('',(#621));
#623=FACE_BOUND('',#622,.T.);
#624=ADVANCED_FACE('F422',(#623),#612,.F.);
#625=CARTESIAN_POINT('',(38.4607954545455,38.1,-0.1524));
#626=DIRECTION('',(0.,0.,1.));
#627=DIRECTION('',(1.,0.,0.));
#628=AXIS2_PLACEMENT_3D('',#625,#626,#627);
#629=PLANE('',#628);
#630=CARTESIAN_POINT('',(38.1,38.1,-0.1524));
#631=DIRECTION('',(0.,0.,-1.));
#632=DIRECTION('',(-1.,0.,0.));
#633=AXIS2_PLACEMENT_3D('',#630,#631,#632);
#634=CIRCLE('',#633,3.96875);
#635=CARTESIAN_POINT('',(34.13125,38.1,-0.1524));
#636=VERTEX_POINT('',#635);
#637=EDGE_CURVE('E219',#636,#636,#634,.T.);
#638=ORIENTED_EDGE('',*,*,#637,.T.);
#639=EDGE_LOOP('',(#638));
#640=FACE_BOUND('',#639,.T.);
#641=ADVANCED_FACE('F426',(#640),#629,.F.);
#642=CARTESIAN_POINT('',(-37.7392045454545,-38.1,-0.1524));
#643=DIRECTION('',(0.,0.,1.));
#644=DIRECTION('',(1.,0.,0.));
#645=AXIS2_PLACEMENT_3D('',#642,#643,#644);
#646=PLANE('',#645);
#647=CARTESIAN_POINT('',(-38.1,-38.1,-0.1524));
#648=DIRECTION('',(0.,0.,-1.));
#649=DIRECTION('',(-1.,0.,0.));
#650=AXIS2_PLACEMENT_3D('',#647,#648,#649);
#651=CIRCLE('',#650,3.96875);
#652=CARTESIAN_POINT('',(-42.06875,-38.1,-0.1524));
#653=VERTEX_POINT('',#652);
#654=EDGE_CURVE('E216',#653,#653,#651,.T.);
#655=ORIENTED_EDGE('',*,*,#654,.T.);
#656=EDGE_LOOP('',(#655));
#657=FACE_BOUND('',#656,.T.);
#658=ADVANCED_FACE('F430',(#657),#646,.F.);
#659=CARTESIAN_POINT('',(0.,0.,-3.5814));
#660=DIRECTION('',(0.,0.,1.));
#661=DIRECTION('',(1.,0.,0.));
#662=AXIS2_PLACEMENT_3D('',#659,#660,#661);
#663=PLANE('',#662);
#664=CARTESIAN_POINT('',(-38.1,0.,-3.5814));
#665=DIRECTION('',(0.,0.,-1.));
#666=DIRECTION('',(-1.,0.,0.));
#667=AXIS2_PLACEMENT_3D('',#664,#665,#666);
#668=CIRCLE('',#667,3.98145);
#669=CARTESIAN_POINT('',(-42.08145,0.,-3.5814));
#670=VERTEX_POINT('',#669);
#671=EDGE_CURVE('E213',#670,#670,#668,.T.);
#672=ORIENTED_EDGE('',*,*,#671,.T.);
#673=EDGE_LOOP('',(#672));
#674=FACE_BOUND('',#673,.T.);
#675=ADVANCED_FACE('F434',(#674),#663,.F.);
#676=CARTESIAN_POINT('',(38.4607954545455,-38.1,-0.1524));
#677=DIRECTION('',(0.,0.,1.));
#678=DIRECTION('',(1.,0.,0.));
#679=AXIS2_PLACEMENT_3D('',#676,#677,#678);
#680=PLANE('',#679);
#681=CARTESIAN_POINT('',(38.1,-38.1,-0.1524));
#682=DIRECTION('',(0.,0.,-1.));
#683=DIRECTION('',(-1.,0.,0.));
#684=AXIS2_PLACEMENT_3D('',#681,#682,#683);
#685=CIRCLE('',#684,3.96875);
#686=CARTESIAN_POINT('',(34.13125,-38.1,-0.1524));
#687=VERTEX_POINT('',#686);
#688=EDGE_CURVE('E189',#687,#687,#685,.T.);
#689=ORIENTED_EDGE('',*,*,#688,.T.);
#690=EDGE_LOOP('',(#689));
#691=FACE_BOUND('',#690,.T.);
#692=ADVANCED_FACE('F438',(#691),#680,.F.);
#693=CARTESIAN_POINT('',(-69.85,44.45,-3.5814));
#694=DIRECTION('',(0.,1.,0.));
#695=DIRECTION('',(0.,0.,1.));
#696=AXIS2_PLACEMENT_3D('',#693,#694,#695);
#697=PLANE('',#696);
#698=DIRECTION('',(1.,0.,0.));
#699=VECTOR('',#698,1.);
#700=CARTESIAN_POINT('',(0.,44.45,-19.05));
#701=LINE('',#700,#699);
#702=CARTESIAN_POINT('',(69.85,44.45,-19.05));
#703=VERTEX_POINT('',#702);
#704=CARTESIAN_POINT('',(-69.85,44.45,-19.05));
#705=VERTEX_POINT('',#704);
#706=EDGE_CURVE('E186',#703,#705,#701,.F.);
#707=ORIENTED_EDGE('',*,*,#706,.T.);
#708=DIRECTION('',(0.,0.,1.));
#709=VECTOR('',#708,1.);
#710=CARTESIAN_POINT('',(-69.85,44.45,-3.5814));
#711=LINE('',#710,#709);
#712=EDGE_CURVE('E159',#548,#705,#711,.F.);
#713=ORIENTED_EDGE('',*,*,#712,.F.);
#714=ORIENTED_EDGE('',*,*,#549,.T.);
#715=DIRECTION('',(0.,0.,-1.));
#716=VECTOR('',#715,1.);
#717=CARTESIAN_POINT('',(69.85,44.45,-3.5814));
#718=LINE('',#717,#716);
#719=EDGE_CURVE('E169',#703,#538,#718,.F.);
#720=ORIENTED_EDGE('',*,*,#719,.F.);
#721=EDGE_LOOP('',(#707,#713,#714,#720));
#722=FACE_BOUND('',#721,.T.);
#723=ADVANCED_FACE('F377',(#722),#697,.T.);
#724=CARTESIAN_POINT('',(-69.85,-44.45,-3.5814));
#725=DIRECTION('',(-1.,0.,0.));
#726=DIRECTION('',(0.,0.,1.));
#727=AXIS2_PLACEMENT_3D('',#724,#725,#726);
#728=PLANE('',#727);
#729=ORIENTED_EDGE('',*,*,#480,.T.);
#730=EDGE_LOOP('',(#729));
#731=FACE_BOUND('',#730,.T.);
#732=ORIENTED_EDGE('',*,*,#460,.T.);
#733=EDGE_LOOP('',(#732));
#734=FACE_BOUND('',#733,.T.);
#735=ORIENTED_EDGE('',*,*,#437,.T.);
#736=EDGE_LOOP('',(#735));
#737=FACE_BOUND('',#736,.T.);
#738=ORIENTED_EDGE('',*,*,#417,.T.);
#739=EDGE_LOOP('',(#738));
#740=FACE_BOUND('',#739,.T.);
#741=ORIENTED_EDGE('',*,*,#397,.T.);
#742=EDGE_LOOP('',(#741));
#743=FACE_BOUND('',#742,.T.);
#744=ORIENTED_EDGE('',*,*,#377,.T.);
#745=EDGE_LOOP('',(#744));
#746=FACE_BOUND('',#745,.T.);
#747=ORIENTED_EDGE('',*,*,#357,.T.);
#748=EDGE_LOOP('',(#747));
#749=FACE_BOUND('',#748,.T.);
#750=ORIENTED_EDGE('',*,*,#337,.T.);
#751=EDGE_LOOP('',(#750));
#752=FACE_BOUND('',#751,.T.);
#753=ORIENTED_EDGE('',*,*,#317,.T.);
#754=EDGE_LOOP('',(#753));
#755=FACE_BOUND('',#754,.T.);
#756=ORIENTED_EDGE('',*,*,#297,.T.);
#757=EDGE_LOOP('',(#756));
#758=FACE_BOUND('',#757,.T.);
#759=DIRECTION('',(0.,1.,0.));
#760=VECTOR('',#759,1.);
#761=CARTESIAN_POINT('',(-69.85,0.,-19.05));
#762=LINE('',#761,#760);
#763=CARTESIAN_POINT('',(-69.85,-44.45,-19.05));
#764=VERTEX_POINT('',#763);
#765=EDGE_CURVE('E183',#705,#764,#762,.F.);
#766=ORIENTED_EDGE('',*,*,#765,.T.);
#767=DIRECTION('',(0.,0.,-1.));
#768=VECTOR('',#767,1.);
#769=CARTESIAN_POINT('',(-69.85,-44.45,-3.5814));
#770=LINE('',#769,#768);
#771=EDGE_CURVE('E163',#556,#764,#770,.T.);
#772=ORIENTED_EDGE('',*,*,#771,.F.);
#773=ORIENTED_EDGE('',*,*,#557,.T.);
#774=ORIENTED_EDGE('',*,*,#712,.T.);
#775=EDGE_LOOP('',(#766,#772,#773,#774));
#776=FACE_BOUND('',#775,.T.);
#777=ADVANCED_FACE('F373',(#731,#734,#737,#740,#743,#746,#749,#752,#755,#758,#776),#728,.T.);
#778=CARTESIAN_POINT('',(69.85,-44.45,-3.5814));
#779=DIRECTION('',(0.,-1.,0.));
#780=DIRECTION('',(0.,0.,-1.));
#781=AXIS2_PLACEMENT_3D('',#778,#779,#780);
#782=PLANE('',#781);
#783=DIRECTION('',(1.,0.,0.));
#784=VECTOR('',#783,1.);
#785=CARTESIAN_POINT('',(0.,-44.45,-19.05));
#786=LINE('',#785,#784);
#787=CARTESIAN_POINT('',(69.85,-44.45,-19.05));
#788=VERTEX_POINT('',#787);
#789=EDGE_CURVE('E180',#764,#788,#786,.T.);
#790=ORIENTED_EDGE('',*,*,#789,.T.);
#791=DIRECTION('',(0.,0.,-1.));
#792=VECTOR('',#791,1.);
#793=CARTESIAN_POINT('',(69.85,-44.45,-3.5814));
#794=LINE('',#793,#792);
#795=EDGE_CURVE('E173',#540,#788,#794,.T.);
#796=ORIENTED_EDGE('',*,*,#795,.F.);
#797=ORIENTED_EDGE('',*,*,#563,.T.);
#798=ORIENTED_EDGE('',*,*,#771,.T.);
#799=EDGE_LOOP('',(#790,#796,#797,#798));
#800=FACE_BOUND('',#799,.T.);
#801=ADVANCED_FACE('F376',(#800),#782,.T.);
#802=CARTESIAN_POINT('',(69.85,44.45,-3.5814));
#803=DIRECTION('',(1.,0.,0.));
#804=DIRECTION('',(0.,0.,-1.));
#805=AXIS2_PLACEMENT_3D('',#802,#803,#804);
#806=PLANE('',#805);
#807=ORIENTED_EDGE('',*,*,#603,.T.);
#808=EDGE_LOOP('',(#807));
#809=FACE_BOUND('',#808,.T.);
#810=ORIENTED_EDGE('',*,*,#583,.T.);
#811=EDGE_LOOP('',(#810));
#812=FACE_BOUND('',#811,.T.);
#813=DIRECTION('',(0.,1.,0.));
#814=VECTOR('',#813,1.);
#815=CARTESIAN_POINT('',(69.85,0.,-19.05));
#816=LINE('',#815,#814);
#817=EDGE_CURVE('E176',#788,#703,#816,.T.);
#818=ORIENTED_EDGE('',*,*,#817,.T.);
#819=ORIENTED_EDGE('',*,*,#719,.T.);
#820=ORIENTED_EDGE('',*,*,#541,.T.);
#821=ORIENTED_EDGE('',*,*,#795,.T.);
#822=EDGE_LOOP('',(#818,#819,#820,#821));
#823=FACE_BOUND('',#822,.T.);
#824=ADVANCED_FACE('F407',(#809,#812,#823),#806,.T.);
#825=CARTESIAN_POINT('',(-38.1,38.1,-0.1524));
#826=DIRECTION('',(0.,0.,-1.));
#827=DIRECTION('',(-1.,0.,0.));
#828=AXIS2_PLACEMENT_3D('',#825,#826,#827);
#829=CYLINDRICAL_SURFACE('',#828,3.96875);
#830=CARTESIAN_POINT('',(-38.1,38.1,-19.05));
#831=DIRECTION('',(0.,0.,-1.));
#832=DIRECTION('',(-1.,0.,0.));
#833=AXIS2_PLACEMENT_3D('',#830,#831,#832);
#834=CIRCLE('',#833,3.96875);
#835=CARTESIAN_POINT('',(-42.06875,38.1,-19.05));
#836=VERTEX_POINT('',#835);
#837=EDGE_CURVE('E179',#836,#836,#834,.T.);
#838=ORIENTED_EDGE('',*,*,#837,.T.);
#839=EDGE_LOOP('',(#838));
#840=FACE_BOUND('',#839,.T.);
#841=ORIENTED_EDGE('',*,*,#620,.F.);
#842=EDGE_LOOP('',(#841));
#843=FACE_BOUND('',#842,.T.);
#844=ADVANCED_FACE('F449',(#840,#843),#829,.F.);
#845=CARTESIAN_POINT('',(38.1,38.1,-0.1524));
#846=DIRECTION('',(0.,0.,-1.));
#847=DIRECTION('',(-1.,0.,0.));
#848=AXIS2_PLACEMENT_3D('',#845,#846,#847);
#849=CYLINDRICAL_SURFACE('',#848,3.96875);
#850=CARTESIAN_POINT('',(38.1,38.1,-19.05));
#851=DIRECTION('',(0.,0.,-1.));
#852=DIRECTION('',(-1.,0.,0.));
#853=AXIS2_PLACEMENT_3D('',#850,#851,#852);
#854=CIRCLE('',#853,3.96875);
#855=CARTESIAN_POINT('',(34.13125,38.1,-19.05));
#856=VERTEX_POINT('',#855);
#857=EDGE_CURVE('E206',#856,#856,#854,.T.);
#858=ORIENTED_EDGE('',*,*,#857,.T.);
#859=EDGE_LOOP('',(#858));
#860=FACE_BOUND('',#859,.T.);
#861=ORIENTED_EDGE('',*,*,#637,.F.);
#862=EDGE_LOOP('',(#861));
#863=FACE_BOUND('',#862,.T.);
#864=ADVANCED_FACE('F453',(#860,#863),#849,.F.);
#865=CARTESIAN_POINT('',(-38.1,-38.1,-0.1524));
#866=DIRECTION('',(0.,0.,-1.));
#867=DIRECTION('',(-1.,0.,0.));
#868=AXIS2_PLACEMENT_3D('',#865,#866,#867);
#869=CYLINDRICAL_SURFACE('',#868,3.96875);
#870=CARTESIAN_POINT('',(-38.1,-38.1,-19.05));
#871=DIRECTION('',(0.,0.,-1.));
#872=DIRECTION('',(-1.,0.,0.));
#873=AXIS2_PLACEMENT_3D('',#870,#871,#872);
#874=CIRCLE('',#873,3.96875);
#875=CARTESIAN_POINT('',(-42.06875,-38.1,-19.05));
#876=VERTEX_POINT('',#875);
#877=EDGE_CURVE('E203',#876,#876,#874,.T.);
#878=ORIENTED_EDGE('',*,*,#877,.T.);
#879=EDGE_LOOP('',(#878));
#880=FACE_BOUND('',#879,.T.);
#881=ORIENTED_EDGE('',*,*,#654,.F.);
#882=EDGE_LOOP('',(#881));
#883=FACE_BOUND('',#882,.T.);
#884=ADVANCED_FACE('F457',(#880,#883),#869,.F.);
#885=CARTESIAN_POINT('',(-38.1,0.,-3.5814));
#886=DIRECTION('',(0.,0.,-1.));
#887=DIRECTION('',(-1.,0.,0.));
#888=AXIS2_PLACEMENT_3D('',#885,#886,#887);
#889=CYLINDRICAL_SURFACE('',#888,3.98145);
#890=CARTESIAN_POINT('',(-38.1,0.,-19.05));
#891=DIRECTION('',(0.,0.,-1.));
#892=DIRECTION('',(-1.,0.,0.));
#893=AXIS2_PLACEMENT_3D('',#890,#891,#892);
#894=CIRCLE('',#893,3.98145);
#895=CARTESIAN_POINT('',(-42.08145,0.,-19.05));
#896=VERTEX_POINT('',#895);
#897=EDGE_CURVE('E200',#896,#896,#894,.T.);
#898=ORIENTED_EDGE('',*,*,#897,.T.);
#899=EDGE_LOOP('',(#898));
#900=FACE_BOUND('',#899,.T.);
#901=ORIENTED_EDGE('',*,*,#671,.F.);
#902=EDGE_LOOP('',(#901));
#903=FACE_BOUND('',#902,.T.);
#904=ADVANCED_FACE('F461',(#900,#903),#889,.F.);
#905=CARTESIAN_POINT('',(38.1,-38.1,-0.1524));
#906=DIRECTION('',(0.,0.,-1.));
#907=DIRECTION('',(-1.,0.,0.));
#908=AXIS2_PLACEMENT_3D('',#905,#906,#907);
#909=CYLINDRICAL_SURFACE('',#908,3.96875);
#910=CARTESIAN_POINT('',(38.1,-38.1,-19.05));
#911=DIRECTION('',(0.,0.,-1.));
#912=DIRECTION('',(-1.,0.,0.));
#913=AXIS2_PLACEMENT_3D('',#910,#911,#912);
#914=CIRCLE('',#913,3.96875);
#915=CARTESIAN_POINT('',(34.13125,-38.1,-19.05));
#916=VERTEX_POINT('',#915);
#917=EDGE_CURVE('E197',#916,#916,#914,.T.);
#918=ORIENTED_EDGE('',*,*,#917,.T.);
#919=EDGE_LOOP('',(#918));
#920=FACE_BOUND('',#919,.T.);
#921=ORIENTED_EDGE('',*,*,#688,.F.);
#922=EDGE_LOOP('',(#921));
#923=FACE_BOUND('',#922,.T.);
#924=ADVANCED_FACE('F465',(#920,#923),#909,.F.);
#925=CARTESIAN_POINT('',(0.,0.,-3.5814));
#926=DIRECTION('',(0.,0.,1.));
#927=DIRECTION('',(1.,0.,0.));
#928=AXIS2_PLACEMENT_3D('',#925,#926,#927);
#929=PLANE('',#928);
#930=CARTESIAN_POINT('',(38.1,0.,-3.5814));
#931=DIRECTION('',(0.,0.,-1.));
#932=DIRECTION('',(-1.,0.,0.));
#933=AXIS2_PLACEMENT_3D('',#930,#931,#932);
#934=CIRCLE('',#933,3.98145);
#935=CARTESIAN_POINT('',(34.11855,0.,-3.5814));
#936=VERTEX_POINT('',#935);
#937=EDGE_CURVE('E194',#936,#936,#934,.T.);
#938=ORIENTED_EDGE('',*,*,#937,.T.);
#939=EDGE_LOOP('',(#938));
#940=FACE_BOUND('',#939,.T.);
#941=ADVANCED_FACE('F340',(#940),#929,.F.);
#942=CARTESIAN_POINT('',(0.,0.,-19.05));
#943=DIRECTION('',(0.,0.,1.));
#944=DIRECTION('',(1.,0.,0.));
#945=AXIS2_PLACEMENT_3D('',#942,#943,#944);
#946=PLANE('',#945);
#947=CARTESIAN_POINT('',(-19.05,0.,-19.05));
#948=DIRECTION('',(0.,0.,-1.));
#949=DIRECTION('',(1.,0.,0.));
#950=AXIS2_PLACEMENT_3D('',#947,#948,#949);
#951=CIRCLE('',#950,3.175);
#952=CARTESIAN_POINT('',(-15.875,0.,-19.05));
#953=VERTEX_POINT('',#952);
#954=EDGE_CURVE('E904',#953,#953,#951,.T.);
#955=ORIENTED_EDGE('',*,*,#954,.F.);
#956=EDGE_LOOP('',(#955));
#957=FACE_BOUND('',#956,.T.);
#958=CARTESIAN_POINT('',(19.05,0.,-19.05));
#959=DIRECTION('',(0.,0.,-1.));
#960=DIRECTION('',(-1.,0.,0.));
#961=AXIS2_PLACEMENT_3D('',#958,#959,#960);
#962=CIRCLE('',#961,3.175);
#963=CARTESIAN_POINT('',(15.875,0.,-19.05));
#964=VERTEX_POINT('',#963);
#965=EDGE_CURVE('E903',#964,#964,#962,.T.);
#966=ORIENTED_EDGE('',*,*,#965,.F.);
#967=EDGE_LOOP('',(#966));
#968=FACE_BOUND('',#967,.T.);
#969=ORIENTED_EDGE('',*,*,#917,.F.);
#970=EDGE_LOOP('',(#969));
#971=FACE_BOUND('',#970,.T.);
#972=ORIENTED_EDGE('',*,*,#897,.F.);
#973=EDGE_LOOP('',(#972));
#974=FACE_BOUND('',#973,.T.);
#975=ORIENTED_EDGE('',*,*,#877,.F.);
#976=EDGE_LOOP('',(#975));
#977=FACE_BOUND('',#976,.T.);
#978=ORIENTED_EDGE('',*,*,#857,.F.);
#979=EDGE_LOOP('',(#978));
#980=FACE_BOUND('',#979,.T.);
#981=ORIENTED_EDGE('',*,*,#837,.F.);
#982=EDGE_LOOP('',(#981));
#983=FACE_BOUND('',#982,.T.);
#984=CARTESIAN_POINT('',(38.1,0.,-19.05));
#985=DIRECTION('',(0.,0.,-1.));
#986=DIRECTION('',(-1.,0.,0.));
#987=AXIS2_PLACEMENT_3D('',#984,#985,#986);
#988=CIRCLE('',#987,3.98145);
#989=CARTESIAN_POINT('',(34.11855,0.,-19.05));
#990=VERTEX_POINT('',#989);
#991=EDGE_CURVE('E190',#990,#990,#988,.F.);
#992=ORIENTED_EDGE('',*,*,#991,.T.);
#993=EDGE_LOOP('',(#992));
#994=FACE_BOUND('',#993,.T.);
#995=ORIENTED_EDGE('',*,*,#789,.F.);
#996=ORIENTED_EDGE('',*,*,#765,.F.);
#997=ORIENTED_EDGE('',*,*,#706,.F.);
#998=ORIENTED_EDGE('',*,*,#817,.F.);
#999=EDGE_LOOP('',(#995,#996,#997,#998));
#1000=FACE_BOUND('',#999,.T.);
#1001=ADVANCED_FACE('F334',(#957,#968,#971,#974,#977,#980,#983,#994,#1000),#946,.F.);
#1002=CARTESIAN_POINT('',(38.1,0.,-3.5814));
#1003=DIRECTION('',(0.,0.,-1.));
#1004=DIRECTION('',(-1.,0.,0.));
#1005=AXIS2_PLACEMENT_3D('',#1002,#1003,#1004);
#1006=CYLINDRICAL_SURFACE('',#1005,3.98145);
#1007=ORIENTED_EDGE('',*,*,#991,.F.);
#1008=EDGE_LOOP('',(#1007));
#1009=FACE_BOUND('',#1008,.T.);
#1010=ORIENTED_EDGE('',*,*,#937,.F.);
#1011=EDGE_LOOP('',(#1010));
#1012=FACE_BOUND('',#1011,.T.);
#1013=ADVANCED_FACE('F331',(#1009,#1012),#1006,.F.);
#1014=CARTESIAN_POINT('',(0.,0.,16.383));
#1015=DIRECTION('',(0.,0.,1.));
#1016=DIRECTION('',(1.,0.,0.));
#1017=AXIS2_PLACEMENT_3D('',#1014,#1015,#1016);
#1018=PLANE('',#1017);
#1019=ORIENTED_EDGE('',*,*,#237,.T.);
#1020=DIRECTION('',(-1.,0.,0.));
#1021=VECTOR('',#1020,1.);
#1022=CARTESIAN_POINT('',(2.93906236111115,0.254,16.383));
#1023=LINE('',#1022,#1021);
#1024=CARTESIAN_POINT('',(-29.7549387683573,0.253999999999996,16.383));
#1025=VERTEX_POINT('',#1024);
#1026=EDGE_CURVE('E109',#227,#1025,#1023,.T.);
#1027=ORIENTED_EDGE('',*,*,#1026,.T.);
#1028=CARTESIAN_POINT('',(0.,0.,16.383));
#1029=DIRECTION('',(0.,0.,1.));
#1030=DIRECTION('',(1.,0.,0.));
#1031=AXIS2_PLACEMENT_3D('',#1028,#1029,#1030);
#1032=CIRCLE('',#1031,29.7560228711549);
#1033=CARTESIAN_POINT('',(0.,-29.7560228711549,16.383));
#1034=VERTEX_POINT('',#1033);
#1035=EDGE_CURVE('E48',#1025,#1034,#1032,.T.);
#1036=ORIENTED_EDGE('',*,*,#1035,.T.);
#1037=DIRECTION('',(0.,-1.,0.));
#1038=VECTOR('',#1037,1.);
#1039=CARTESIAN_POINT('',(0.,2.667,16.383));
#1040=LINE('',#1039,#1038);
#1041=CARTESIAN_POINT('',(0.,-30.,16.383));
#1042=VERTEX_POINT('',#1041);
#1043=EDGE_CURVE('E142',#1034,#1042,#1040,.T.);
#1044=ORIENTED_EDGE('',*,*,#1043,.T.);
#1045=CARTESIAN_POINT('',(0.,0.,16.383));
#1046=DIRECTION('',(0.,0.,1.));
#1047=DIRECTION('',(1.,0.,0.));
#1048=AXIS2_PLACEMENT_3D('',#1045,#1046,#1047);
#1049=CIRCLE('',#1048,30.);
#1050=CARTESIAN_POINT('',(29.8812166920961,2.667,16.383));
#1051=VERTEX_POINT('',#1050);
#1052=EDGE_CURVE('E136',#1042,#1051,#1049,.T.);
#1053=ORIENTED_EDGE('',*,*,#1052,.T.);
#1054=DIRECTION('',(-1.,0.,0.));
#1055=VECTOR('',#1054,1.);
#1056=CARTESIAN_POINT('',(0.,2.667,16.383));
#1057=LINE('',#1056,#1055);
#1058=EDGE_CURVE('E139',#1051,#236,#1057,.T.);
#1059=ORIENTED_EDGE('',*,*,#1058,.T.);
#1060=EDGE_LOOP('',(#1019,#1027,#1036,#1044,#1053,#1059));
#1061=FACE_BOUND('',#1060,.T.);
#1062=ADVANCED_FACE('F111',(#1061),#1018,.T.);
#1063=CARTESIAN_POINT('',(0.,2.667,16.383));
#1064=DIRECTION('',(-1.,0.,0.));
#1065=DIRECTION('',(0.,0.,1.));
#1066=AXIS2_PLACEMENT_3D('',#1063,#1064,#1065);
#1067=PLANE('',#1066);
#1068=ORIENTED_EDGE('',*,*,#1043,.F.);
#1069=DIRECTION('',(0.,0.,1.));
#1070=VECTOR('',#1069,1.);
#1071=CARTESIAN_POINT('',(0.,-29.7560228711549,16.383));
#1072=LINE('',#1071,#1070);
#1073=EDGE_CURVE('E11',#1034,#498,#1072,.T.);
#1074=ORIENTED_EDGE('',*,*,#1073,.T.);
#1075=ORIENTED_EDGE('',*,*,#529,.T.);
#1076=DIRECTION('',(0.,0.,1.));
#1077=VECTOR('',#1076,1.);
#1078=CARTESIAN_POINT('',(0.,-30.,16.383));
#1079=LINE('',#1078,#1077);
#1080=EDGE_CURVE('E148',#1042,#522,#1079,.T.);
#1081=ORIENTED_EDGE('',*,*,#1080,.F.);
#1082=EDGE_LOOP('',(#1068,#1074,#1075,#1081));
#1083=FACE_BOUND('',#1082,.T.);
#1084=ADVANCED_FACE('F300',(#1083),#1067,.F.);
#1085=CARTESIAN_POINT('',(0.,2.667,16.383));
#1086=DIRECTION('',(0.,1.,0.));
#1087=DIRECTION('',(0.,0.,1.));
#1088=AXIS2_PLACEMENT_3D('',#1085,#1086,#1087);
#1089=PLANE('',#1088);
#1090=ORIENTED_EDGE('',*,*,#1058,.F.);
#1091=DIRECTION('',(0.,0.,1.));
#1092=VECTOR('',#1091,1.);
#1093=CARTESIAN_POINT('',(29.8812166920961,2.667,16.383));
#1094=LINE('',#1093,#1092);
#1095=EDGE_CURVE('E144',#1051,#513,#1094,.T.);
#1096=ORIENTED_EDGE('',*,*,#1095,.T.);
#1097=ORIENTED_EDGE('',*,*,#514,.T.);
#1098=ORIENTED_EDGE('',*,*,#243,.F.);
#1099=EDGE_LOOP('',(#1090,#1096,#1097,#1098));
#1100=FACE_BOUND('',#1099,.T.);
#1101=ADVANCED_FACE('F310',(#1100),#1089,.F.);
#1102=CARTESIAN_POINT('',(0.,0.,16.383));
#1103=DIRECTION('',(0.,0.,1.));
#1104=DIRECTION('',(1.,0.,0.));
#1105=AXIS2_PLACEMENT_3D('',#1102,#1103,#1104);
#1106=CYLINDRICAL_SURFACE('',#1105,30.);
#1107=ORIENTED_EDGE('',*,*,#523,.T.);
#1108=ORIENTED_EDGE('',*,*,#1095,.F.);
#1109=ORIENTED_EDGE('',*,*,#1052,.F.);
#1110=ORIENTED_EDGE('',*,*,#1080,.T.);
#1111=EDGE_LOOP('',(#1107,#1108,#1109,#1110));
#1112=FACE_BOUND('',#1111,.T.);
#1113=ADVANCED_FACE('F303',(#1112),#1106,.F.);
#1114=CARTESIAN_POINT('',(2.93906236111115,0.254,16.383));
#1115=DIRECTION('',(0.,1.,0.));
#1116=DIRECTION('',(-1.,0.,0.));
#1117=AXIS2_PLACEMENT_3D('',#1114,#1115,#1116);
#1118=PLANE('',#1117);
#1119=ORIENTED_EDGE('',*,*,#505,.T.);
#1120=DIRECTION('',(0.,0.,1.));
#1121=VECTOR('',#1120,1.);
#1122=CARTESIAN_POINT('',(-29.7549387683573,0.253999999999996,16.383));
#1123=LINE('',#1122,#1121);
#1124=EDGE_CURVE('E119',#1025,#496,#1123,.T.);
#1125=ORIENTED_EDGE('',*,*,#1124,.F.);
#1126=ORIENTED_EDGE('',*,*,#1026,.F.);
#1127=ORIENTED_EDGE('',*,*,#228,.F.);
#1128=EDGE_LOOP('',(#1119,#1125,#1126,#1127));
#1129=FACE_BOUND('',#1128,.T.);
#1130=ADVANCED_FACE('F120',(#1129),#1118,.F.);
#1131=CARTESIAN_POINT('',(0.,0.,16.383));
#1132=DIRECTION('',(0.,0.,1.));
#1133=DIRECTION('',(1.,0.,0.));
#1134=AXIS2_PLACEMENT_3D('',#1131,#1132,#1133);
#1135=CYLINDRICAL_SURFACE('',#1134,29.7560228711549);
#1136=ORIENTED_EDGE('',*,*,#1035,.F.);
#1137=ORIENTED_EDGE('',*,*,#1124,.T.);
#1138=ORIENTED_EDGE('',*,*,#499,.T.);
#1139=ORIENTED_EDGE('',*,*,#1073,.F.);
#1140=EDGE_LOOP('',(#1136,#1137,#1138,#1139));
#1141=FACE_BOUND('',#1140,.T.);
#1142=ADVANCED_FACE('F127',(#1141),#1135,.F.);
#1143=CARTESIAN_POINT('',(19.05,0.,-12.7));
#1144=DIRECTION('',(0.,0.,-1.));
#1145=DIRECTION('',(-1.,0.,0.));
#1146=AXIS2_PLACEMENT_3D('',#1143,#1144,#1145);
#1147=CYLINDRICAL_SURFACE('',#1146,3.175);
#1148=CARTESIAN_POINT('',(19.05,0.,-12.7));
#1149=DIRECTION('',(0.,0.,-1.));
#1150=DIRECTION('',(-1.,0.,0.));
#1151=AXIS2_PLACEMENT_3D('',#1148,#1149,#1150);
#1152=CIRCLE('',#1151,3.175);
#1153=CARTESIAN_POINT('',(15.875,0.,-12.7));
#1154=VERTEX_POINT('',#1153);
#1155=EDGE_CURVE('E133',#1154,#1154,#1152,.T.);
#1156=ORIENTED_EDGE('',*,*,#1155,.F.);
#1157=EDGE_LOOP('',(#1156));
#1158=FACE_BOUND('',#1157,.T.);
#1159=ORIENTED_EDGE('',*,*,#965,.T.);
#1160=EDGE_LOOP('',(#1159));
#1161=FACE_BOUND('',#1160,.T.);
#1162=ADVANCED_FACE('F493',(#1158,#1161),#1147,.F.);
#1163=CARTESIAN_POINT('',(19.05,0.,-12.7));
#1164=DIRECTION('',(0.,0.,-1.));
#1165=DIRECTION('',(-1.,0.,0.));
#1166=AXIS2_PLACEMENT_3D('',#1163,#1164,#1165);
#1167=PLANE('',#1166);
#1168=ORIENTED_EDGE('',*,*,#1155,.T.);
#1169=EDGE_LOOP('',(#1168));
#1170=FACE_BOUND('',#1169,.T.);
#1171=ADVANCED_FACE('F498',(#1170),#1167,.T.);
#1172=CARTESIAN_POINT('',(-19.05,0.,-12.7));
#1173=DIRECTION('',(0.,0.,-1.));
#1174=DIRECTION('',(-1.,0.,0.));
#1175=AXIS2_PLACEMENT_3D('',#1172,#1173,#1174);
#1176=CYLINDRICAL_SURFACE('',#1175,3.175);
#1177=CARTESIAN_POINT('',(-19.05,0.,-12.7));
#1178=DIRECTION('',(0.,0.,-1.));
#1179=DIRECTION('',(1.,0.,0.));
#1180=AXIS2_PLACEMENT_3D('',#1177,#1178,#1179);
#1181=CIRCLE('',#1180,3.175);
#1182=CARTESIAN_POINT('',(-15.875,0.,-12.7));
#1183=VERTEX_POINT('',#1182);
#1184=EDGE_CURVE('E902',#1183,#1183,#1181,.T.);
#1185=ORIENTED_EDGE('',*,*,#1184,.F.);
#1186=EDGE_LOOP('',(#1185));
#1187=FACE_BOUND('',#1186,.T.);
#1188=ORIENTED_EDGE('',*,*,#954,.T.);
#1189=EDGE_LOOP('',(#1188));
#1190=FACE_BOUND('',#1189,.T.);
#1191=ADVANCED_FACE('F508',(#1187,#1190),#1176,.F.);
#1192=CARTESIAN_POINT('',(-19.05,0.,-12.7));
#1193=DIRECTION('',(0.,0.,1.));
#1194=DIRECTION('',(1.,0.,0.));
#1195=AXIS2_PLACEMENT_3D('',#1192,#1193,#1194);
#1196=PLANE('',#1195);
#1197=ORIENTED_EDGE('',*,*,#1184,.T.);
#1198=EDGE_LOOP('',(#1197));
#1199=FACE_BOUND('',#1198,.T.);
#1200=ADVANCED_FACE('F518',(#1199),#1196,.F.);
#1201=CLOSED_SHELL('',(#35,#52,#69,#86,#103,#120,#137,#154,#171,#188,#205,#250,#267,#284,#304,
#324,#344,#364,#384,#404,#424,#444,#464,#484,#567,#587,#607,#624,#641,#658,#675,#692,#723,#777,
#801,#824,#844,#864,#884,#904,#924,#941,#1001,#1013,#1062,#1084,#1101,#1113,#1130,#1142,#1162,
#1171,#1191,#1200));
#1202=MANIFOLD_SOLID_BREP('B2',#1201);
#1203=ADVANCED_BREP_SHAPE_REPRESENTATION('',(#18,#1202),#14);
#1204=SHAPE_DEFINITION_REPRESENTATION(#9,#1203);
ENDSEC;
END-ISO-10303-21;
